# Generated by FakeRAM 2.0
VERSION 5.7 ;
BUSBITCHARS "[]" ;
PROPERTYDEFINITIONS
  MACRO width INTEGER ;
  MACRO depth INTEGER ;
  MACRO banks INTEGER ;
END PROPERTYDEFINITIONS
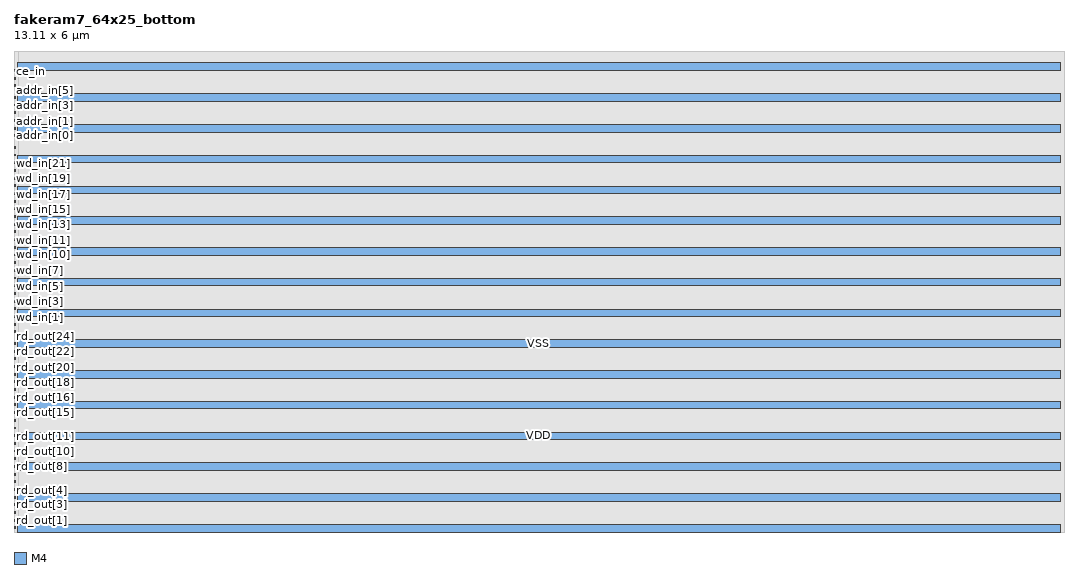
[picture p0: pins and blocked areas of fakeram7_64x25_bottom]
MACRO fakeram7_64x25_bottom
  PROPERTY width 25 ;
  PROPERTY depth 64 ;
  PROPERTY banks 4 ;
  FOREIGN fakeram7_64x25_bottom 0 0 ;
  SYMMETRY X Y R90 ;
  SIZE 13.110 BY 6.000 ;
  CLASS BLOCK ;
  PIN rd_out[0]
    DIRECTION OUTPUT ;
    USE SIGNAL ;
    SHAPE ABUTMENT ;
    PORT
      LAYER M4 ;
      RECT 0.000 0.039 0.024 0.063 ;
    END
  END rd_out[0]
  PIN rd_out[1]
    DIRECTION OUTPUT ;
    USE SIGNAL ;
    SHAPE ABUTMENT ;
    PORT
      LAYER M4 ;
      RECT 0.000 0.135 0.024 0.159 ;
    END
  END rd_out[1]
  PIN rd_out[2]
    DIRECTION OUTPUT ;
    USE SIGNAL ;
    SHAPE ABUTMENT ;
    PORT
      LAYER M4 ;
      RECT 0.000 0.231 0.024 0.255 ;
    END
  END rd_out[2]
  PIN rd_out[3]
    DIRECTION OUTPUT ;
    USE SIGNAL ;
    SHAPE ABUTMENT ;
    PORT
      LAYER M4 ;
      RECT 0.000 0.327 0.024 0.351 ;
    END
  END rd_out[3]
  PIN rd_out[4]
    DIRECTION OUTPUT ;
    USE SIGNAL ;
    SHAPE ABUTMENT ;
    PORT
      LAYER M4 ;
      RECT 0.000 0.423 0.024 0.447 ;
    END
  END rd_out[4]
  PIN rd_out[5]
    DIRECTION OUTPUT ;
    USE SIGNAL ;
    SHAPE ABUTMENT ;
    PORT
      LAYER M4 ;
      RECT 0.000 0.519 0.024 0.543 ;
    END
  END rd_out[5]
  PIN rd_out[6]
    DIRECTION OUTPUT ;
    USE SIGNAL ;
    SHAPE ABUTMENT ;
    PORT
      LAYER M4 ;
      RECT 0.000 0.615 0.024 0.639 ;
    END
  END rd_out[6]
  PIN rd_out[7]
    DIRECTION OUTPUT ;
    USE SIGNAL ;
    SHAPE ABUTMENT ;
    PORT
      LAYER M4 ;
      RECT 0.000 0.711 0.024 0.735 ;
    END
  END rd_out[7]
  PIN rd_out[8]
    DIRECTION OUTPUT ;
    USE SIGNAL ;
    SHAPE ABUTMENT ;
    PORT
      LAYER M4 ;
      RECT 0.000 0.807 0.024 0.831 ;
    END
  END rd_out[8]
  PIN rd_out[9]
    DIRECTION OUTPUT ;
    USE SIGNAL ;
    SHAPE ABUTMENT ;
    PORT
      LAYER M4 ;
      RECT 0.000 0.903 0.024 0.927 ;
    END
  END rd_out[9]
  PIN rd_out[10]
    DIRECTION OUTPUT ;
    USE SIGNAL ;
    SHAPE ABUTMENT ;
    PORT
      LAYER M4 ;
      RECT 0.000 0.999 0.024 1.023 ;
    END
  END rd_out[10]
  PIN rd_out[11]
    DIRECTION OUTPUT ;
    USE SIGNAL ;
    SHAPE ABUTMENT ;
    PORT
      LAYER M4 ;
      RECT 0.000 1.095 0.024 1.119 ;
    END
  END rd_out[11]
  PIN rd_out[12]
    DIRECTION OUTPUT ;
    USE SIGNAL ;
    SHAPE ABUTMENT ;
    PORT
      LAYER M4 ;
      RECT 0.000 1.191 0.024 1.215 ;
    END
  END rd_out[12]
  PIN rd_out[13]
    DIRECTION OUTPUT ;
    USE SIGNAL ;
    SHAPE ABUTMENT ;
    PORT
      LAYER M4 ;
      RECT 0.000 1.287 0.024 1.311 ;
    END
  END rd_out[13]
  PIN rd_out[14]
    DIRECTION OUTPUT ;
    USE SIGNAL ;
    SHAPE ABUTMENT ;
    PORT
      LAYER M4 ;
      RECT 0.000 1.383 0.024 1.407 ;
    END
  END rd_out[14]
  PIN rd_out[15]
    DIRECTION OUTPUT ;
    USE SIGNAL ;
    SHAPE ABUTMENT ;
    PORT
      LAYER M4 ;
      RECT 0.000 1.479 0.024 1.503 ;
    END
  END rd_out[15]
  PIN rd_out[16]
    DIRECTION OUTPUT ;
    USE SIGNAL ;
    SHAPE ABUTMENT ;
    PORT
      LAYER M4 ;
      RECT 0.000 1.575 0.024 1.599 ;
    END
  END rd_out[16]
  PIN rd_out[17]
    DIRECTION OUTPUT ;
    USE SIGNAL ;
    SHAPE ABUTMENT ;
    PORT
      LAYER M4 ;
      RECT 0.000 1.671 0.024 1.695 ;
    END
  END rd_out[17]
  PIN rd_out[18]
    DIRECTION OUTPUT ;
    USE SIGNAL ;
    SHAPE ABUTMENT ;
    PORT
      LAYER M4 ;
      RECT 0.000 1.767 0.024 1.791 ;
    END
  END rd_out[18]
  PIN rd_out[19]
    DIRECTION OUTPUT ;
    USE SIGNAL ;
    SHAPE ABUTMENT ;
    PORT
      LAYER M4 ;
      RECT 0.000 1.863 0.024 1.887 ;
    END
  END rd_out[19]
  PIN rd_out[20]
    DIRECTION OUTPUT ;
    USE SIGNAL ;
    SHAPE ABUTMENT ;
    PORT
      LAYER M4 ;
      RECT 0.000 1.959 0.024 1.983 ;
    END
  END rd_out[20]
  PIN rd_out[21]
    DIRECTION OUTPUT ;
    USE SIGNAL ;
    SHAPE ABUTMENT ;
    PORT
      LAYER M4 ;
      RECT 0.000 2.055 0.024 2.079 ;
    END
  END rd_out[21]
  PIN rd_out[22]
    DIRECTION OUTPUT ;
    USE SIGNAL ;
    SHAPE ABUTMENT ;
    PORT
      LAYER M4 ;
      RECT 0.000 2.151 0.024 2.175 ;
    END
  END rd_out[22]
  PIN rd_out[23]
    DIRECTION OUTPUT ;
    USE SIGNAL ;
    SHAPE ABUTMENT ;
    PORT
      LAYER M4 ;
      RECT 0.000 2.247 0.024 2.271 ;
    END
  END rd_out[23]
  PIN rd_out[24]
    DIRECTION OUTPUT ;
    USE SIGNAL ;
    SHAPE ABUTMENT ;
    PORT
      LAYER M4 ;
      RECT 0.000 2.343 0.024 2.367 ;
    END
  END rd_out[24]
  PIN wd_in[0]
    DIRECTION INPUT ;
    USE SIGNAL ;
    SHAPE ABUTMENT ;
    PORT
      LAYER M4 ;
      RECT 0.000 2.487 0.024 2.511 ;
    END
  END wd_in[0]
  PIN wd_in[1]
    DIRECTION INPUT ;
    USE SIGNAL ;
    SHAPE ABUTMENT ;
    PORT
      LAYER M4 ;
      RECT 0.000 2.583 0.024 2.607 ;
    END
  END wd_in[1]
  PIN wd_in[2]
    DIRECTION INPUT ;
    USE SIGNAL ;
    SHAPE ABUTMENT ;
    PORT
      LAYER M4 ;
      RECT 0.000 2.679 0.024 2.703 ;
    END
  END wd_in[2]
  PIN wd_in[3]
    DIRECTION INPUT ;
    USE SIGNAL ;
    SHAPE ABUTMENT ;
    PORT
      LAYER M4 ;
      RECT 0.000 2.775 0.024 2.799 ;
    END
  END wd_in[3]
  PIN wd_in[4]
    DIRECTION INPUT ;
    USE SIGNAL ;
    SHAPE ABUTMENT ;
    PORT
      LAYER M4 ;
      RECT 0.000 2.871 0.024 2.895 ;
    END
  END wd_in[4]
  PIN wd_in[5]
    DIRECTION INPUT ;
    USE SIGNAL ;
    SHAPE ABUTMENT ;
    PORT
      LAYER M4 ;
      RECT 0.000 2.967 0.024 2.991 ;
    END
  END wd_in[5]
  PIN wd_in[6]
    DIRECTION INPUT ;
    USE SIGNAL ;
    SHAPE ABUTMENT ;
    PORT
      LAYER M4 ;
      RECT 0.000 3.063 0.024 3.087 ;
    END
  END wd_in[6]
  PIN wd_in[7]
    DIRECTION INPUT ;
    USE SIGNAL ;
    SHAPE ABUTMENT ;
    PORT
      LAYER M4 ;
      RECT 0.000 3.159 0.024 3.183 ;
    END
  END wd_in[7]
  PIN wd_in[8]
    DIRECTION INPUT ;
    USE SIGNAL ;
    SHAPE ABUTMENT ;
    PORT
      LAYER M4 ;
      RECT 0.000 3.255 0.024 3.279 ;
    END
  END wd_in[8]
  PIN wd_in[9]
    DIRECTION INPUT ;
    USE SIGNAL ;
    SHAPE ABUTMENT ;
    PORT
      LAYER M4 ;
      RECT 0.000 3.351 0.024 3.375 ;
    END
  END wd_in[9]
  PIN wd_in[10]
    DIRECTION INPUT ;
    USE SIGNAL ;
    SHAPE ABUTMENT ;
    PORT
      LAYER M4 ;
      RECT 0.000 3.447 0.024 3.471 ;
    END
  END wd_in[10]
  PIN wd_in[11]
    DIRECTION INPUT ;
    USE SIGNAL ;
    SHAPE ABUTMENT ;
    PORT
      LAYER M4 ;
      RECT 0.000 3.543 0.024 3.567 ;
    END
  END wd_in[11]
  PIN wd_in[12]
    DIRECTION INPUT ;
    USE SIGNAL ;
    SHAPE ABUTMENT ;
    PORT
      LAYER M4 ;
      RECT 0.000 3.639 0.024 3.663 ;
    END
  END wd_in[12]
  PIN wd_in[13]
    DIRECTION INPUT ;
    USE SIGNAL ;
    SHAPE ABUTMENT ;
    PORT
      LAYER M4 ;
      RECT 0.000 3.735 0.024 3.759 ;
    END
  END wd_in[13]
  PIN wd_in[14]
    DIRECTION INPUT ;
    USE SIGNAL ;
    SHAPE ABUTMENT ;
    PORT
      LAYER M4 ;
      RECT 0.000 3.831 0.024 3.855 ;
    END
  END wd_in[14]
  PIN wd_in[15]
    DIRECTION INPUT ;
    USE SIGNAL ;
    SHAPE ABUTMENT ;
    PORT
      LAYER M4 ;
      RECT 0.000 3.927 0.024 3.951 ;
    END
  END wd_in[15]
  PIN wd_in[16]
    DIRECTION INPUT ;
    USE SIGNAL ;
    SHAPE ABUTMENT ;
    PORT
      LAYER M4 ;
      RECT 0.000 4.023 0.024 4.047 ;
    END
  END wd_in[16]
  PIN wd_in[17]
    DIRECTION INPUT ;
    USE SIGNAL ;
    SHAPE ABUTMENT ;
    PORT
      LAYER M4 ;
      RECT 0.000 4.119 0.024 4.143 ;
    END
  END wd_in[17]
  PIN wd_in[18]
    DIRECTION INPUT ;
    USE SIGNAL ;
    SHAPE ABUTMENT ;
    PORT
      LAYER M4 ;
      RECT 0.000 4.215 0.024 4.239 ;
    END
  END wd_in[18]
  PIN wd_in[19]
    DIRECTION INPUT ;
    USE SIGNAL ;
    SHAPE ABUTMENT ;
    PORT
      LAYER M4 ;
      RECT 0.000 4.311 0.024 4.335 ;
    END
  END wd_in[19]
  PIN wd_in[20]
    DIRECTION INPUT ;
    USE SIGNAL ;
    SHAPE ABUTMENT ;
    PORT
      LAYER M4 ;
      RECT 0.000 4.407 0.024 4.431 ;
    END
  END wd_in[20]
  PIN wd_in[21]
    DIRECTION INPUT ;
    USE SIGNAL ;
    SHAPE ABUTMENT ;
    PORT
      LAYER M4 ;
      RECT 0.000 4.503 0.024 4.527 ;
    END
  END wd_in[21]
  PIN wd_in[22]
    DIRECTION INPUT ;
    USE SIGNAL ;
    SHAPE ABUTMENT ;
    PORT
      LAYER M4 ;
      RECT 0.000 4.599 0.024 4.623 ;
    END
  END wd_in[22]
  PIN wd_in[23]
    DIRECTION INPUT ;
    USE SIGNAL ;
    SHAPE ABUTMENT ;
    PORT
      LAYER M4 ;
      RECT 0.000 4.695 0.024 4.719 ;
    END
  END wd_in[23]
  PIN wd_in[24]
    DIRECTION INPUT ;
    USE SIGNAL ;
    SHAPE ABUTMENT ;
    PORT
      LAYER M4 ;
      RECT 0.000 4.791 0.024 4.815 ;
    END
  END wd_in[24]
  PIN addr_in[0]
    DIRECTION INPUT ;
    USE SIGNAL ;
    SHAPE ABUTMENT ;
    PORT
      LAYER M4 ;
      RECT 0.000 4.935 0.024 4.959 ;
    END
  END addr_in[0]
  PIN addr_in[1]
    DIRECTION INPUT ;
    USE SIGNAL ;
    SHAPE ABUTMENT ;
    PORT
      LAYER M4 ;
      RECT 0.000 5.031 0.024 5.055 ;
    END
  END addr_in[1]
  PIN addr_in[2]
    DIRECTION INPUT ;
    USE SIGNAL ;
    SHAPE ABUTMENT ;
    PORT
      LAYER M4 ;
      RECT 0.000 5.127 0.024 5.151 ;
    END
  END addr_in[2]
  PIN addr_in[3]
    DIRECTION INPUT ;
    USE SIGNAL ;
    SHAPE ABUTMENT ;
    PORT
      LAYER M4 ;
      RECT 0.000 5.223 0.024 5.247 ;
    END
  END addr_in[3]
  PIN addr_in[4]
    DIRECTION INPUT ;
    USE SIGNAL ;
    SHAPE ABUTMENT ;
    PORT
      LAYER M4 ;
      RECT 0.000 5.319 0.024 5.343 ;
    END
  END addr_in[4]
  PIN addr_in[5]
    DIRECTION INPUT ;
    USE SIGNAL ;
    SHAPE ABUTMENT ;
    PORT
      LAYER M4 ;
      RECT 0.000 5.415 0.024 5.439 ;
    END
  END addr_in[5]
  PIN we_in
    DIRECTION INPUT ;
    USE SIGNAL ;
    SHAPE ABUTMENT ;
    PORT
      LAYER M4 ;
      RECT 0.000 5.559 0.024 5.583 ;
    END
  END we_in
  PIN ce_in
    DIRECTION INPUT ;
    USE SIGNAL ;
    SHAPE ABUTMENT ;
    PORT
      LAYER M4 ;
      RECT 0.000 5.655 0.024 5.679 ;
    END
  END ce_in
  PIN clk
    DIRECTION INPUT ;
    USE SIGNAL ;
    SHAPE ABUTMENT ;
    PORT
      LAYER M4 ;
      RECT 0.000 5.751 0.024 5.775 ;
    END
  END clk
  PIN VSS
    DIRECTION INOUT ;
    USE GROUND ;
    PORT
      LAYER M4 ;
      RECT 0.048 0.000 13.062 0.096 ;
      RECT 0.048 0.768 13.062 0.864 ;
      RECT 0.048 1.536 13.062 1.632 ;
      RECT 0.048 2.304 13.062 2.400 ;
      RECT 0.048 3.072 13.062 3.168 ;
      RECT 0.048 3.840 13.062 3.936 ;
      RECT 0.048 4.608 13.062 4.704 ;
      RECT 0.048 5.376 13.062 5.472 ;
    END
  END VSS
  PIN VDD
    DIRECTION INOUT ;
    USE POWER ;
    PORT
      LAYER M4 ;
      RECT 0.048 0.384 13.062 0.480 ;
      RECT 0.048 1.152 13.062 1.248 ;
      RECT 0.048 1.920 13.062 2.016 ;
      RECT 0.048 2.688 13.062 2.784 ;
      RECT 0.048 3.456 13.062 3.552 ;
      RECT 0.048 4.224 13.062 4.320 ;
      RECT 0.048 4.992 13.062 5.088 ;
      RECT 0.048 5.760 13.062 5.856 ;
    END
  END VDD
  OBS
    LAYER M1 ;
    RECT 0 0 13.110 6.000 ;
    LAYER M2 ;
    RECT 0 0 13.110 6.000 ;
    LAYER M3 ;
    RECT 0.059 0.000 13.110 6.000 ;
    LAYER M4 ;
    RECT 0.059 0.000 13.110 6.000 ;
  END
END fakeram7_64x25_bottom

END LIBRARY
